! (c) 2009  Infineon Technologies AG, Munich
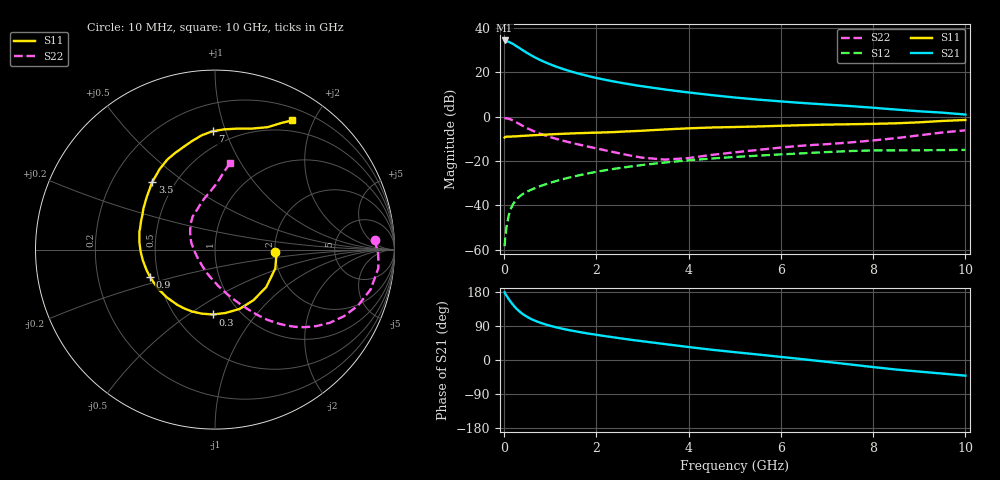
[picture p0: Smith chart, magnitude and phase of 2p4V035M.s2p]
! Infineon Technologies  Discrete & RF Semiconductors
! BFP420
! VCE =  4.0 V,  IC =  35 mA
! Common Emitter S-Parameters:  Nov 2009
# GHz  S  MA  R  50
!  f  S11  S21  S12  S22
! GHz  MAG  ANG  MAG  ANG  MAG  ANG  MAG  ANG
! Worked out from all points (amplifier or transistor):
!   46 points, 10 MHz to 10 GHz, reference 50 ohm
!   highest |S21| = 34.3 dB at 10 MHz (marker M1)
!   |S21| within 3 dB of that: start of sweep to 300.4 MHz
!   unconditionally stable (mu >= 1): start of sweep to 19.75 MHz; 1.485 GHz to end of sweep
!   at 300 MHz: K = 0.46, MSG = 34.0 dB, |S12| = -36.7 dB
!   at 1.7 GHz: K = 1.04, MAG = 21.4 dB, |S12| = -26.1 dB
!   at 10 GHz: K = 1.06, MAG = 6.5 dB, |S12| = -15.0 dB
!   lowest NFmin = 1.64 dB at 900 MHz
!   S11 on the Smith chart (normalised r, x): 10 MHz: 2.01, -0.05; 300 MHz: 0.75, -0.63; 900 MHz: 0.45, -0.16; 3.5 GHz: 0.37, +0.38; 7 GHz: 0.39, +0.90; 10 GHz: 0.35, +1.71
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0.01  0.3361 -2.0  52 178.8  0.0012 67.8  0.8916 3.5
0.02  0.3438 -6.8  50.57 175.6  0.0017 74.5  0.9099 -1.6
0.05  0.352 -17.4  49.84 170.0  0.0032 72.2  0.9158 -6.5
0.1  0.3536 -36.3  48.3 160.7  0.006 73.6  0.8953 -14.3
0.15  0.3542 -53.0  45.75 152.1  0.0086 71.0  0.8563 -21.3
0.2  0.3576 -67.6  42.86 144.5  0.0109 68.4  0.8088 -27.3
0.25  0.3579 -80.7  39.71 137.5  0.0129 66.1  0.7588 -32.5
0.3  0.3618 -92.0  36.84 131.5  0.0147 64.3  0.7092 -36.9
0.4  0.3679 -110.2  31.52 121.6  0.0178 61.8  0.6207 -43.9
0.5  0.3725 -124.1  27.13 113.7  0.0204 60.5  0.5475 -49.1
0.6  0.378 -135.1  23.61 107.3  0.0228 59.8  0.4893 -53.2
0.7  0.3834 -143.8  20.79 102.1  0.0252 59.7  0.4423 -56.4
0.9  0.3925 -157.2  16.61 93.7  0.0298 59.7  0.3721 -61.7
1.1  0.4011 -167.2  13.71 87.1  0.0346 59.7  0.3211 -66.5
1.3  0.4102 -175.2  11.61 81.5  0.0395 59.3  0.2819 -71.1
1.7  0.4251 171.9  8.823 72.4  0.0494 57.7  0.2244 -80.4
2.4  0.4485 154.4  6.121 59.3  0.0668 52.7  0.1559 -99.6
3.5  0.5139 132.9  4.062 41.7  0.0925 42.9  0.1072 -152.1
5.5  0.5987 106.9  2.417 14.5  0.1317 24.0  0.1772 141.3
7  0.6593 91.2  1.864 -4.9  0.1586 9.8  0.2392 115.9
8.5  0.7063 72.7  1.438 -25.2  0.1735 -7.3  0.3272 94.2
10  0.8388 59.1  1.112 -41.3  0.1777 -18.7  0.4895 80.0
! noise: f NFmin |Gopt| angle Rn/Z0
0.9  1.64  0.3  -155  0.13
1.8  1.9  0.37  -142  0.15
2.4  2.1  0.34  -134  0.19
3  2.11  0.4  -126  0.22
4  2.25  0.5  -110  0.35
5  2.73  0.54  -94  0.59
6  3.16  0.59  -82  0.84
